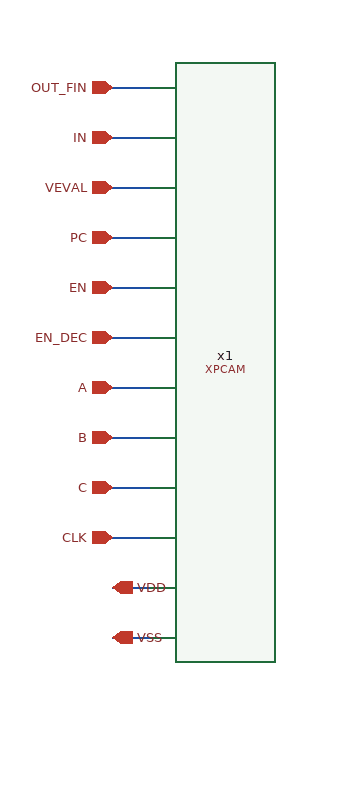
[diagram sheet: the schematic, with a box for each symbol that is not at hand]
v {xschem version=3.4.6 file_version=1.2}
G {}
K {}
V {}
S {}
E {}
N -170 -210 -140 -210 {lab=OUT_FIN}
N -170 -170 -140 -170 {lab=IN}
N -170 -130 -140 -130 {lab=VEVAL}
N -170 -90 -140 -90 {lab=PC}
N -170 -50 -140 -50 {lab=EN}
N -170 -10 -140 -10 {lab=EN_DEC}
N -170 30 -140 30 {lab=A}
N -170 70 -140 70 {lab=B}
N -170 110 -140 110 {lab=C}
N -170 150 -140 150 {lab=CLK}
N -170 190 -140 190 {lab=VDD}
N -170 230 -140 230 {lab=VSS}
C {XPCAM.sym} -170 290 0 0 {name=x1}
C {ipin.sym} -170 -10 0 0 {name=p16 lab=EN_DEC}
C {ipin.sym} -170 -50 0 0 {name=p1 lab=EN}
C {ipin.sym} -170 150 0 0 {name=p2 lab=CLK}
C {ipin.sym} -170 -90 0 0 {name=p3 lab=PC}
C {ipin.sym} -170 -130 0 0 {name=p4 lab=VEVAL}
C {ipin.sym} -170 -170 0 0 {name=p5 lab=IN}
C {ipin.sym} -170 30 0 0 {name=p6 lab=A}
C {ipin.sym} -170 70 0 0 {name=p7 lab=B}
C {ipin.sym} -170 110 0 0 {name=p8 lab=C}
C {opin.sym} -170 -210 0 1 {name=p9 lab=OUT_FIN}
C {iopin.sym} -170 190 0 1 {name=p10 lab=VDD}
C {iopin.sym} -170 230 0 1 {name=p11 lab=VSS}
